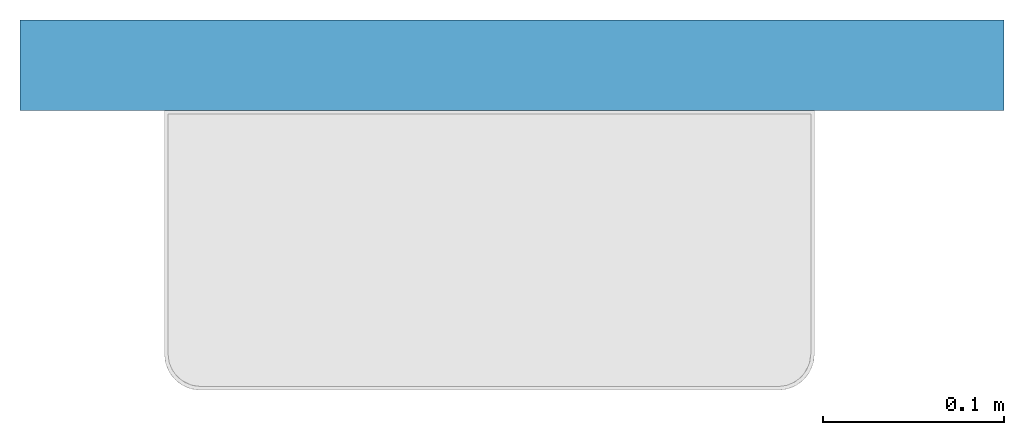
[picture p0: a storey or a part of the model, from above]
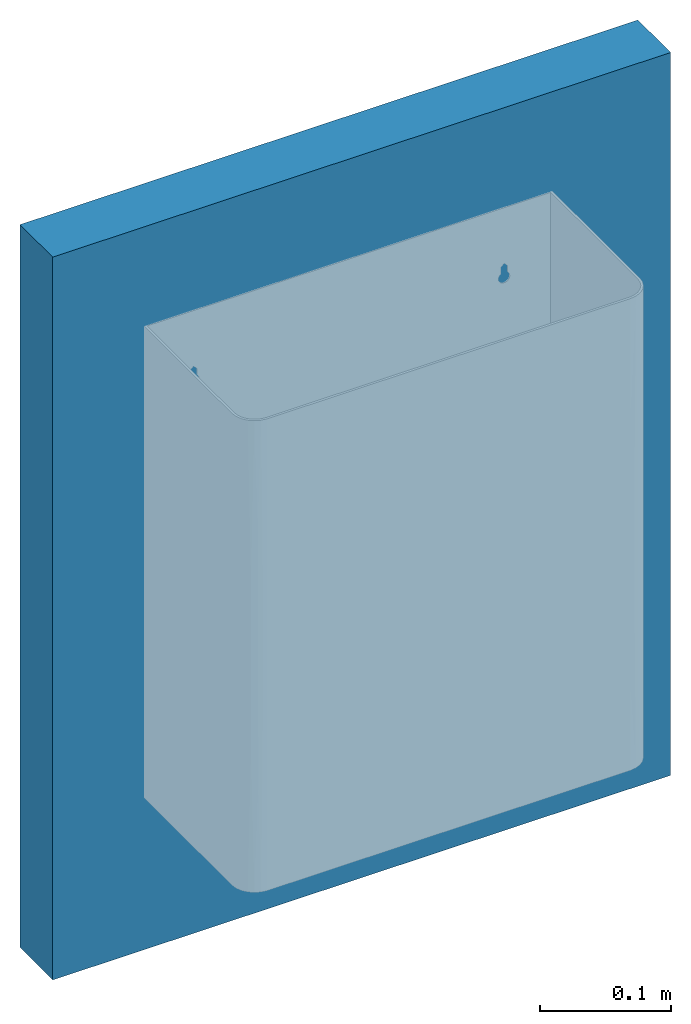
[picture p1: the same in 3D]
Properties of the parts of a building model (IFC2X3)

# File
Description: ViewDefinition [CoordinationView]
Time: 2016-10-20T14:58:16
Written by: The EXPRESS Data Manager Version 5.01.0100.02.64mod : 6 Jun 2012
Made in: 20140709_2115(x64) - Exporter 2014.0.2014.0709 - Default UI
Comment: STEP Physical File produced by: The EXPRESS Data Manager Version 5.01.0100.02.64mod : 6 Jun 2012 * Module: EDMstepFileFactory/EDMstandAlone * Creation date: Thu Oct 20 14:58:16 2016 * Host: BIM-HP * Database: C:\Users\dcole\AppData\Local\Temp\{3C14A89C-E7B0-48C1-8195-F8C80F2474AE}\ifc * Database version: 5507 * Database creation date: Thu Oct 20 14:58:15 2016 * Schema: IFC2X3 * Model: DataRepository.ifc * Model creation date: Thu Oct 20 14:58:16 2016 * Header model: DataRepository.ifc_HeaderModel * Header model creation date: Thu Oct 20 14:58:16 2016 * EDMuser: sdai-user * EDMgroup: sdai-group * License ID and type: 5605 : Permanent license. Expiry date: * EDMstepFileFactory options: 020000

# IfcProject
LongName: P:\Fastrack\53721_BELL-CHEM\ADDITIONAL DRAWINGS 2016 BIM\IFC\BC921.ifc

# IfcSite, Default
RefLatitude: 42, 24, 53, 508911; RefLongitude: -71, -15, -29, -58837; RefElevation: 0 mm

# IfcBuilding
Pset_BuildingCommon - NumberOfStoreys: 1

# IfcBuildingStorey, Level 1
LongName: Level 1; Elevation: 0 mm
Constraints - Elevation Base: Project Base Point; Elevation: 0 mm
Identity Data - Name: Level 1; Building Story: yes; Structural: no
Dimensions - Computation Height: 0 mm
Graphics - Line Pattern: -3000010; Symbol at End 2 Default: yes; Symbol at End 1 Default: no; Line Weight: 1; Color: 0

# IfcBuildingElementProxy: BC921 Dolphin Stainless Steel Surface Mounted Bin, BC921:BC921 Dolphin Stainless Steel Surface Mounted Bin:28206
In: Level 1
Material: Stainless Steel
Constraints - Host: Level : Level 1; Offset: -199.585 mm; Moves With Nearby Elements: no; Level: Level: Level 1
Phasing - Phase Created: New Construction
Dimensions - Volume: 0.0011571 m3; Height: 440mm; Width: 360mm; Projection: 155mm
Pset_ManufacturerTypeInformation - Manufacturer: Dolphin Solutions Ltd.
Pset_BuildingElementProxyCommon - Reference: BC921 Dolphin Stainless Steel Surface Mounted Bin
Identity Data - Email: info@dolphinsolutions.co.uk; Assembly Code: D2010900; Tel No.: +44 (0) 1424 202 224; Fax No.: +44 (0) 1424 205 200; Type Comments: Wire bin for this product = BC921-1; Description: Stainless steel surface mounted bin; Model: BC921; URL: www.dolphinsolutions.co.uk; Address: Southpoint, Compass Park, Junction Road, Bodiam, TN32 5BS; Manufacturer: Dolphin Solutions Ltd.; Assembly Description: Other Plumbing Fixtures
General - Product Page Link: https://www.dolphinsolutions.co.uk/product/stainless-steel-surface-mounted-bins-2/; Capacity Bin: 24 litre; Product Data: High quality satin stainless steel. Wall mounted. Open top. Internal wire basket available A BC921-1 wire bin can be used in this bin. 24 litre capacity.

# IfcWallStandardCase: Basic Wall:Wall 1, Basic Wall:Wall 1:3092
In: Level 1
Type - PredefinedType: STANDARD; Material: Default Wall 50 mm
Type - Analytical Properties - Roughness: 1; Absorptance: 0.1
Type - Construction - Width: 50 mm; Wrapping at Inserts: Do not wrap; Function: Exterior
Type - Graphics - Coarse Scale Fill Color: 8454143
Phasing - Phase Created: New Construction
Constraints - Unconnected Height: 674.032 mm; Base Offset: -341.935 mm; Base Constraint: Level: Level 1; Top Offset: 0 mm; Top is Attached: no; Location Line: Finish Face: Interior; Related to Mass: no; Base is Attached: no; Top Extension Distance: 0 mm; Base Extension Distance: 0 mm; Room Bounding: yes
Structural - Enable Analytical Model: no; Structural: no; Structural Usage: Non-bearing
Dimensions - Volume: 0.0183674 m3; Area: 0.367348 m2; Length: 545 mm
Pset_WallCommon - Reference: Wall 1; LoadBearing: no; ExtendToStructure: no; IsExternal: yes
